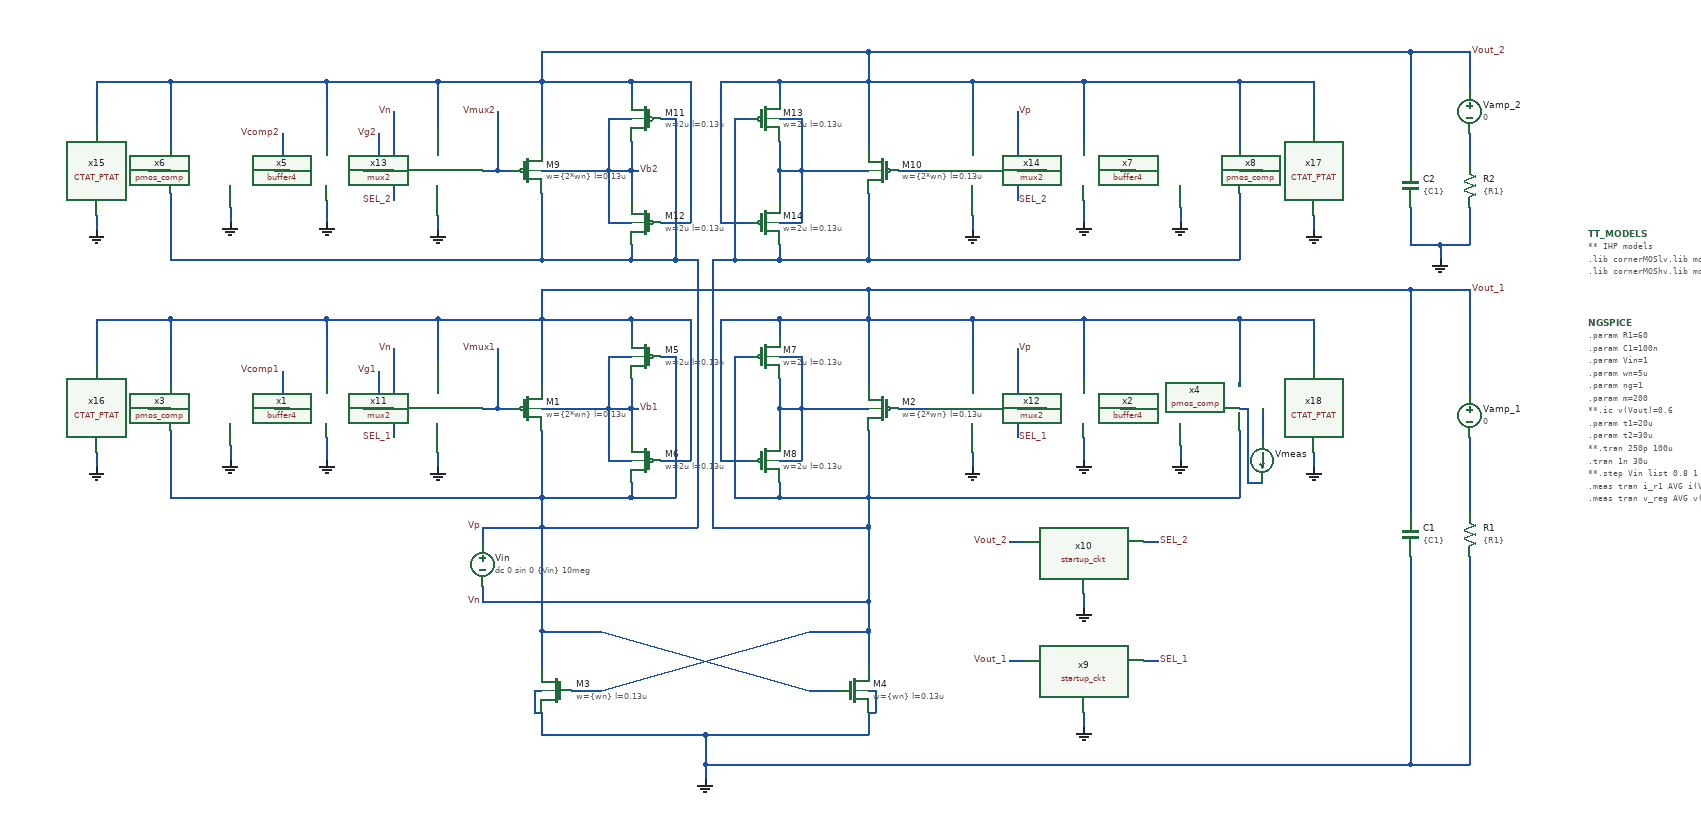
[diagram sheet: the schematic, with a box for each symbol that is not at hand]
v {xschem version=3.4.7 file_version=1.2}
G {}
K {}
V {}
S {}
E {}
P 4 1 1260 -1420 {}
N 870 -750 870 -730 {lab=Vout_1}
N 870 -530 870 -510 {lab=Vp}
N 910 -700 930 -700 {lab=Vp}
N 910 -560 950 -560 {lab=Vout_1}
N 1010 -700 1030 -700 {lab=Vn}
N 1070 -530 1070 -510 {lab=Vn}
N 1070 -750 1070 -730 {lab=Vout_1}
N 990 -560 1030 -560 {lab=Vout_1}
N 1070 -630 1070 -590 {lab=#net1}
N 1070 -670 1070 -630 {lab=#net1}
N 870 -630 870 -590 {lab=Vb1}
N 840 -630 870 -630 {lab=Vb1}
N 870 -670 870 -630 {lab=Vb1}
N 750 -750 870 -750 {lab=Vout_1}
N 1070 -750 1190 -750 {lab=Vout_1}
N 750 -750 750 -660 {lab=Vout_1}
N 1190 -750 1190 -660 {lab=Vout_1}
N 930 -700 930 -510 {lab=Vp}
N 870 -510 930 -510 {lab=Vp}
N 750 -510 870 -510 {lab=Vp}
N 750 -600 750 -510 {lab=Vp}
N 1070 -510 1190 -510 {lab=Vn}
N 1190 -600 1190 -510 {lab=Vn}
N 1010 -700 1010 -510 {lab=Vn}
N 1010 -510 1070 -510 {lab=Vn}
N 990 -750 990 -560 {lab=Vout_1}
N 990 -750 1070 -750 {lab=Vout_1}
N 950 -750 950 -560 {lab=Vout_1}
N 870 -750 950 -750 {lab=Vout_1}
N 970 -190 1190 -190 {lab=GND}
N 1190 -330 1190 -280 {lab=Vn}
N 750 -330 750 -280 {lab=Vp}
N 790 -250 830 -250 {lab=Vn}
N 1110 -250 1150 -250 {lab=Vp}
N 830 -250 1110 -330 {lab=Vn}
N 830 -330 1110 -250 {lab=Vp}
N 750 -330 830 -330 {lab=Vp}
N 750 -470 750 -330 {lab=Vp}
N 1110 -330 1190 -330 {lab=Vn}
N 1190 -370 1190 -330 {lab=Vn}
N 670 -390 670 -370 {lab=Vn}
N 670 -370 1190 -370 {lab=Vn}
N 1190 -470 1190 -370 {lab=Vn}
N 670 -470 670 -450 {lab=Vp}
N 670 -470 750 -470 {lab=Vp}
N 750 -510 750 -470 {lab=Vp}
N 840 -700 870 -700 {lab=Vb1}
N 840 -700 840 -630 {lab=Vb1}
N 840 -560 870 -560 {lab=Vb1}
N 840 -630 840 -560 {lab=Vb1}
N 1070 -700 1100 -700 {lab=#net1}
N 1100 -700 1100 -630 {lab=#net1}
N 1070 -630 1100 -630 {lab=#net1}
N 1070 -560 1100 -560 {lab=#net1}
N 1100 -630 1100 -560 {lab=#net1}
N 400 -630 410 -630 {lab=Vcomp1}
N 250 -600 250 -510 {lab=Vp}
N 250 -750 250 -660 {lab=Vout_1}
N 460 -750 460 -670 {lab=Vout_1}
N 250 -750 460 -750 {lab=Vout_1}
N 750 -790 750 -750 {lab=Vout_1}
N 750 -790 1190 -790 {lab=Vout_1}
N 1190 -790 1190 -750 {lab=Vout_1}
N 970 -150 970 -130 {lab=GND}
N 750 -190 970 -190 {lab=GND}
N 1920 -430 1920 -150 {lab=GND}
N 2000 -430 2000 -150 {lab=GND}
N 1920 -150 2000 -150 {lab=GND}
N 1920 -790 1920 -490 {lab=Vout_1}
N 2000 -590 2000 -490 {lab=#net2}
N 2000 -790 2000 -650 {lab=Vout_1}
N 1190 -250 1200 -250 {lab=GND}
N 1200 -250 1200 -220 {lab=GND}
N 1190 -220 1200 -220 {lab=GND}
N 1190 -220 1190 -190 {lab=GND}
N 750 -220 750 -190 {lab=GND}
N 740 -250 750 -250 {lab=GND}
N 740 -250 740 -220 {lab=GND}
N 740 -220 750 -220 {lab=GND}
N 1100 -630 1190 -630 {lab=#net1}
N 750 -630 840 -630 {lab=Vb1}
N 530 -680 530 -630 {lab=Vg1}
N 510 -630 530 -630 {lab=Vg1}
N 400 -680 400 -630 {lab=Vcomp1}
N 390 -630 400 -630 {lab=Vcomp1}
N 870 -630 880 -630 {lab=Vb1}
N 460 -590 460 -560 {lab=GND}
N 330 -580 330 -560 {lab=GND}
N 250 -510 750 -510 {lab=Vp}
N 610 -750 750 -750 {lab=Vout_1}
N 530 -630 550 -630 {lab=Vg1}
N 550 -710 550 -650 {lab=Vn}
N 550 -610 550 -590 {lab=SEL_1}
N 690 -630 710 -630 {lab=Vmux1}
N 690 -710 690 -630 {lab=Vmux1}
N 670 -630 690 -630 {lab=Vmux1}
N 610 -570 610 -550 {lab=GND}
N 610 -750 610 -690 {lab=Vout_1}
N 460 -750 610 -750 {lab=Vout_1}
N 1530 -630 1550 -630 {lab=#net3}
N 1690 -600 1690 -510 {lab=Vn}
N 1690 -750 1690 -660 {lab=Vout_1}
N 1480 -750 1480 -670 {lab=Vout_1}
N 1480 -750 1690 -750 {lab=Vout_1}
N 1480 -590 1480 -560 {lab=GND}
N 1610 -580 1610 -560 {lab=GND}
N 1190 -510 1690 -510 {lab=Vn}
N 1190 -750 1330 -750 {lab=Vout_1}
N 1390 -630 1430 -630 {lab=#net4}
N 1390 -610 1390 -590 {lab=SEL_1}
N 1230 -630 1270 -630 {lab=#net5}
N 1330 -570 1330 -550 {lab=GND}
N 1330 -750 1330 -690 {lab=Vout_1}
N 1330 -750 1480 -750 {lab=Vout_1}
N 1390 -710 1390 -650 {lab=Vp}
N 870 -1070 870 -1050 {lab=Vout_2}
N 870 -850 870 -830 {lab=Vp}
N 910 -1020 930 -1020 {lab=Vp}
N 910 -880 950 -880 {lab=Vout_2}
N 1010 -1020 1030 -1020 {lab=Vn}
N 1070 -850 1070 -830 {lab=Vn}
N 1070 -1070 1070 -1050 {lab=Vout_2}
N 990 -880 1030 -880 {lab=Vout_2}
N 1070 -950 1070 -910 {lab=#net6}
N 1070 -990 1070 -950 {lab=#net6}
N 870 -950 870 -910 {lab=Vb2}
N 840 -950 870 -950 {lab=Vb2}
N 870 -990 870 -950 {lab=Vb2}
N 750 -1070 870 -1070 {lab=Vout_2}
N 1070 -1070 1190 -1070 {lab=Vout_2}
N 750 -1070 750 -980 {lab=Vout_2}
N 1190 -1070 1190 -980 {lab=Vout_2}
N 930 -1020 930 -830 {lab=Vp}
N 870 -830 930 -830 {lab=Vp}
N 750 -830 870 -830 {lab=Vp}
N 750 -920 750 -830 {lab=Vp}
N 1070 -830 1190 -830 {lab=Vn}
N 1190 -920 1190 -830 {lab=Vn}
N 1010 -1020 1010 -830 {lab=Vn}
N 1010 -830 1070 -830 {lab=Vn}
N 990 -1070 990 -880 {lab=Vout_2}
N 990 -1070 1070 -1070 {lab=Vout_2}
N 950 -1070 950 -880 {lab=Vout_2}
N 870 -1070 950 -1070 {lab=Vout_2}
N 840 -1020 870 -1020 {lab=Vb2}
N 840 -1020 840 -950 {lab=Vb2}
N 840 -880 870 -880 {lab=Vb2}
N 840 -950 840 -880 {lab=Vb2}
N 1070 -1020 1100 -1020 {lab=#net6}
N 1100 -1020 1100 -950 {lab=#net6}
N 1070 -950 1100 -950 {lab=#net6}
N 1070 -880 1100 -880 {lab=#net6}
N 1100 -950 1100 -880 {lab=#net6}
N 400 -950 410 -950 {lab=Vcomp2}
N 250 -920 250 -830 {lab=Vp}
N 250 -1070 250 -980 {lab=Vout_2}
N 460 -1070 460 -990 {lab=Vout_2}
N 1100 -950 1190 -950 {lab=#net6}
N 750 -950 840 -950 {lab=Vb2}
N 530 -1000 530 -950 {lab=Vg2}
N 510 -950 530 -950 {lab=Vg2}
N 400 -1000 400 -950 {lab=Vcomp2}
N 390 -950 400 -950 {lab=Vcomp2}
N 870 -950 880 -950 {lab=Vb2}
N 460 -910 460 -880 {lab=GND}
N 330 -900 330 -880 {lab=GND}
N 250 -830 750 -830 {lab=Vp}
N 610 -1070 750 -1070 {lab=Vout_2}
N 530 -950 550 -950 {lab=Vg2}
N 550 -1030 550 -970 {lab=Vn}
N 550 -930 550 -910 {lab=SEL_2}
N 690 -950 710 -950 {lab=Vmux2}
N 690 -1030 690 -950 {lab=Vmux2}
N 670 -950 690 -950 {lab=Vmux2}
N 610 -890 610 -870 {lab=GND}
N 610 -1070 610 -1010 {lab=Vout_2}
N 460 -1070 610 -1070 {lab=Vout_2}
N 1530 -950 1550 -950 {lab=#net7}
N 1690 -920 1690 -830 {lab=Vn}
N 1690 -1070 1690 -980 {lab=Vout_2}
N 1480 -1070 1480 -990 {lab=Vout_2}
N 1480 -1070 1690 -1070 {lab=Vout_2}
N 1480 -910 1480 -880 {lab=GND}
N 1610 -900 1610 -880 {lab=GND}
N 1190 -830 1690 -830 {lab=Vn}
N 1190 -1070 1330 -1070 {lab=Vout_2}
N 1390 -950 1430 -950 {lab=#net8}
N 1390 -930 1390 -910 {lab=SEL_2}
N 1230 -950 1270 -950 {lab=#net9}
N 1330 -890 1330 -870 {lab=GND}
N 1330 -1070 1330 -1010 {lab=Vout_2}
N 1330 -1070 1480 -1070 {lab=Vout_2}
N 1390 -1030 1390 -970 {lab=Vp}
N 750 -470 960 -470 {lab=Vp}
N 930 -830 960 -830 {lab=Vp}
N 960 -830 960 -470 {lab=Vp}
N 980 -830 1010 -830 {lab=Vn}
N 980 -830 980 -470 {lab=Vn}
N 980 -470 1190 -470 {lab=Vn}
N 1190 -510 1190 -470 {lab=Vn}
N 1960 -850 2000 -850 {lab=GND}
N 1960 -850 1960 -830 {lab=GND}
N 1920 -850 1960 -850 {lab=GND}
N 970 -190 970 -150 {lab=GND}
N 1480 -380 1480 -360 {lab=GND}
N 1480 -220 1480 -200 {lab=GND}
N 1380 -290 1400 -290 {lab=Vout_1}
N 1380 -450 1400 -450 {lab=Vout_2}
N 1560 -450 1580 -450 {lab=SEL_2}
N 1560 -290 1580 -290 {lab=SEL_1}
N 2000 -900 2000 -850 {lab=GND}
N 1920 -900 1920 -850 {lab=GND}
N 1920 -1110 1920 -960 {lab=Vout_2}
N 2000 -1000 2000 -960 {lab=#net10}
N 2000 -1110 2000 -1060 {lab=Vout_2}
N 750 -1110 750 -1070 {lab=Vout_2}
N 1190 -1110 1920 -1110 {lab=Vout_2}
N 1190 -1110 1190 -1070 {lab=Vout_2}
N 750 -1110 1190 -1110 {lab=Vout_2}
N 150 -570 150 -550 {lab=GND}
N 150 -750 150 -690 {lab=Vout_1}
N 150 -750 250 -750 {lab=Vout_1}
N 220 -630 250 -630 {lab=#net11}
N 1790 -570 1790 -550 {lab=GND}
N 1190 -790 1920 -790 {lab=Vout_1}
N 1920 -790 2000 -790 {lab=Vout_1}
N 970 -150 1920 -150 {lab=GND}
N 1920 -1110 2000 -1110 {lab=Vout_2}
N 150 -890 150 -870 {lab=GND}
N 150 -1070 150 -1010 {lab=Vout_2}
N 250 -1070 460 -1070 {lab=Vout_2}
N 150 -1070 250 -1070 {lab=Vout_2}
N 220 -950 250 -950 {lab=#net12}
N 1790 -890 1790 -870 {lab=GND}
N 1790 -1070 1790 -1010 {lab=Vout_2}
N 1690 -1070 1790 -1070 {lab=Vout_2}
N 1690 -950 1720 -950 {lab=#net13}
N 1790 -750 1790 -690 {lab=Vout_1}
N 1690 -750 1790 -750 {lab=Vout_1}
N 1720 -630 1720 -590 {lab=#net14}
N 1700 -530 1720 -530 {lab=#net15}
N 1700 -630 1700 -530 {lab=#net15}
N 1690 -630 1700 -630 {lab=#net15}
C {sg13g2_pr/sg13_lv_pmos.sym} 730 -630 0 0 {name=M1
l=0.13u
w=\{2*wn\}
ng=\{ng\}
m=\{m\}
model=sg13_lv_pmos
spiceprefix=X
}
C {sg13g2_pr/sg13_lv_pmos.sym} 1210 -630 0 1 {name=M2
l=0.13u
w=\{2*wn\}
ng=\{ng\}
m=\{m\}
model=sg13_lv_pmos
spiceprefix=X
}
C {sg13g2_pr/sg13_lv_nmos.sym} 770 -250 0 1 {name=M3
l=0.13u
w=\{wn\}
ng=\{ng\}
m=\{m\}
model=sg13_lv_nmos
spiceprefix=X
}
C {sg13g2_pr/sg13_lv_nmos.sym} 1170 -250 0 0 {name=M4
l=0.13u
w=\{wn\}
ng=\{ng\}
m=\{m\}
model=sg13_lv_nmos
spiceprefix=X
}
C {sg13g2_pr/sg13_lv_pmos.sym} 890 -700 0 1 {name=M5
l=0.13u
w=2u
ng=1
m=1
model=sg13_lv_pmos
spiceprefix=X
}
C {sg13g2_pr/sg13_lv_pmos.sym} 890 -560 2 0 {name=M6
l=0.13u
w=2u
ng=1
m=1
model=sg13_lv_pmos
spiceprefix=X
}
C {sg13g2_pr/sg13_lv_pmos.sym} 1050 -700 0 0 {name=M7
l=0.13u
w=2u
ng=1
m=1
model=sg13_lv_pmos
spiceprefix=X
}
C {sg13g2_pr/sg13_lv_pmos.sym} 1050 -560 2 1 {name=M8
l=0.13u
w=2u
ng=1
m=1
model=sg13_lv_pmos
spiceprefix=X
}
C {vsource.sym} 670 -420 0 1 {name=Vin value="dc 0 sin 0 \{Vin\} 10meg" savecurrent=false}
C {lab_pin.sym} 670 -470 0 0 {name=p1 sig_type=std_logic lab=Vp}
C {lab_pin.sym} 670 -370 0 0 {name=p2 sig_type=std_logic lab=Vn}
C {gnd.sym} 150 -550 0 0 {name=l1 lab=GND}
C {capa.sym} 1920 -460 0 0 {name=C1
m=1
value=\{C1\}
footprint=1206
device="ceramic capacitor"}
C {res.sym} 2000 -460 0 0 {name=R1
value=\{R1\}
footprint=1206
device=resistor
m=1}
C {vsource.sym} 2000 -620 0 0 {name=Vamp_1 value=0 savecurrent=false}
C {lab_pin.sym} 2000 -790 0 1 {name=p3 sig_type=std_logic lab=Vout_1}
C {gnd.sym} 970 -130 0 0 {name=l3 lab=GND}
C {lab_pin.sym} 400 -680 0 0 {name=p4 sig_type=std_logic lab=Vcomp1}
C {lab_pin.sym} 530 -680 0 0 {name=p5 sig_type=std_logic lab=Vg1}
C {lab_pin.sym} 880 -630 0 1 {name=p6 sig_type=std_logic lab=Vb1}
C {gnd.sym} 330 -560 0 0 {name=l4 lab=GND}
C {gnd.sym} 460 -560 0 0 {name=l5 lab=GND}
C {code_shown.sym} 2160 -865 0 0 {
name=TT_MODELS
only_toplevel=true
value="
** IHP models
.lib cornerMOSlv.lib mos_tt
.lib cornerMOShv.lib mos_tt
"
spice_ignore=false
      }
C {code_shown.sym} 2160 -745 0 0 {name=NGSPICE
only_toplevel=false
value="
.param R1=60
.param C1=100n
.param Vin=1
.param wn=5u
.param ng=1
.param m=200
**.ic v(Vout)=0.6
.param t1=20u
.param t2=30u
**.tran 250p 100u
.tran 1n 30u
**.step Vin list 0.8 1
.meas tran i_r1 AVG i(Vamp_1) from=t1 to=t2
.meas tran v_reg AVG v(vout_1) from=t1 to=t2
.meas tran p_out AVG par('((v(Vout_1)**2)/R1)+((v(Vout_2)**2)/R1)') from=t1 to=t2
.meas tran p_in AVG par('-(v(Vp)-v(Vn))*i(Vin)') from=t1 to=t2
.meas tran PCE param='p_out/p_in' from=t1 to=t2
.meas tran VCR param='v_reg/Vin'
.save all
"}
C {lab_pin.sym} 550 -590 0 0 {name=p7 sig_type=std_logic lab=SEL_1}
C {lab_pin.sym} 550 -710 0 0 {name=p8 sig_type=std_logic lab=Vn}
C {lab_pin.sym} 690 -710 0 0 {name=p9 sig_type=std_logic lab=Vmux1}
C {gnd.sym} 610 -550 0 0 {name=l8 lab=GND}
C {gnd.sym} 1790 -550 0 1 {name=l2 lab=GND}
C {gnd.sym} 1610 -560 0 1 {name=l6 lab=GND}
C {gnd.sym} 1480 -560 0 1 {name=l7 lab=GND}
C {lab_pin.sym} 1390 -590 0 1 {name=p12 sig_type=std_logic lab=SEL_1}
C {gnd.sym} 1330 -550 0 1 {name=l9 lab=GND}
C {lab_pin.sym} 1390 -710 0 1 {name=p10 sig_type=std_logic lab=Vp}
C {sg13g2_pr/sg13_lv_pmos.sym} 730 -950 0 0 {name=M9
l=0.13u
w=\{2*wn\}
ng=\{ng\}
m=\{m\}
model=sg13_lv_pmos
spiceprefix=X
}
C {sg13g2_pr/sg13_lv_pmos.sym} 1210 -950 0 1 {name=M10
l=0.13u
w=\{2*wn\}
ng=\{ng\}
m=\{m\}
model=sg13_lv_pmos
spiceprefix=X
}
C {sg13g2_pr/sg13_lv_pmos.sym} 890 -1020 0 1 {name=M11
l=0.13u
w=2u
ng=1
m=1
model=sg13_lv_pmos
spiceprefix=X
}
C {sg13g2_pr/sg13_lv_pmos.sym} 890 -880 2 0 {name=M12
l=0.13u
w=2u
ng=1
m=1
model=sg13_lv_pmos
spiceprefix=X
}
C {sg13g2_pr/sg13_lv_pmos.sym} 1050 -1020 0 0 {name=M13
l=0.13u
w=2u
ng=1
m=1
model=sg13_lv_pmos
spiceprefix=X
}
C {sg13g2_pr/sg13_lv_pmos.sym} 1050 -880 2 1 {name=M14
l=0.13u
w=2u
ng=1
m=1
model=sg13_lv_pmos
spiceprefix=X
}
C {lab_pin.sym} 400 -1000 0 0 {name=p11 sig_type=std_logic lab=Vcomp2}
C {lab_pin.sym} 530 -1000 0 0 {name=p13 sig_type=std_logic lab=Vg2}
C {lab_pin.sym} 880 -950 0 1 {name=p14 sig_type=std_logic lab=Vb2}
C {gnd.sym} 330 -880 0 0 {name=l11 lab=GND}
C {gnd.sym} 460 -880 0 0 {name=l12 lab=GND}
C {lab_pin.sym} 550 -910 0 0 {name=p15 sig_type=std_logic lab=SEL_2}
C {lab_pin.sym} 550 -1030 0 0 {name=p16 sig_type=std_logic lab=Vn}
C {lab_pin.sym} 690 -1030 0 0 {name=p17 sig_type=std_logic lab=Vmux2}
C {gnd.sym} 610 -870 0 0 {name=l13 lab=GND}
C {gnd.sym} 1610 -880 0 1 {name=l14 lab=GND}
C {gnd.sym} 1480 -880 0 1 {name=l15 lab=GND}
C {lab_pin.sym} 1390 -910 0 1 {name=p18 sig_type=std_logic lab=SEL_2}
C {gnd.sym} 1330 -870 0 1 {name=l16 lab=GND}
C {lab_pin.sym} 1390 -1030 0 1 {name=p19 sig_type=std_logic lab=Vp}
C {capa.sym} 1920 -930 0 0 {name=C2
m=1
value=\{C1\}
footprint=1206
device="ceramic capacitor"}
C {res.sym} 2000 -930 0 0 {name=R2
value=\{R1\}
footprint=1206
device=resistor
m=1}
C {vsource.sym} 2000 -1030 0 0 {name=Vamp_2 value=0 savecurrent=false}
C {gnd.sym} 1960 -830 0 1 {name=l18 lab=GND}
C {lab_pin.sym} 2000 -1110 0 1 {name=p20 sig_type=std_logic lab=Vout_2}
C {gnd.sym} 1480 -360 0 1 {name=l19 lab=GND}
C {gnd.sym} 1480 -200 0 1 {name=l20 lab=GND}
C {lab_pin.sym} 1380 -290 0 0 {name=p21 sig_type=std_logic lab=Vout_1}
C {lab_pin.sym} 1380 -450 0 0 {name=p22 sig_type=std_logic lab=Vout_2}
C {lab_pin.sym} 1580 -290 0 1 {name=p23 sig_type=std_logic lab=SEL_1}
C {lab_pin.sym} 1580 -450 0 1 {name=p24 sig_type=std_logic lab=SEL_2}
C {gnd.sym} 150 -870 0 0 {name=l10 lab=GND}
C {gnd.sym} 1790 -870 0 1 {name=l17 lab=GND}
C {SSDOR_1V_v1/components/buffer4/buffer4.sym} 390 -550 0 0 {name=x1 wn=1u}
C {SSDOR_1V_v1/components/buffer4/buffer4.sym} 1550 -550 0 1 {name=x2 wn=1u}
C {SSDOR_1V_v1/components/buffer4/buffer4.sym} 390 -870 0 0 {name=x5 wn=1u}
C {SSDOR_1V_v1/components/buffer4/buffer4.sym} 1550 -870 0 1 {name=x7 wn=1u}
C {SSDOR_1V_v1/components/pmos_comp/pmos_comp.sym} 230 -560 0 0 {name=x3}
C {SSDOR_1V_v1/components/pmos_comp/pmos_comp.sym} 1710 -560 0 1 {name=x4}
C {SSDOR_1V_v1/components/pmos_comp/pmos_comp.sym} 230 -880 0 0 {name=x6}
C {SSDOR_1V_v1/components/pmos_comp/pmos_comp.sym} 1710 -880 0 1 {name=x8}
C {SSDOR_1V_v1/components/mux2/mux2.sym} 610 -630 0 0 {name=x11}
C {SSDOR_1V_v1/components/mux2/mux2.sym} 1330 -630 0 1 {name=x12}
C {SSDOR_1V_v1/components/mux2/mux2.sym} 610 -950 0 0 {name=x13}
C {SSDOR_1V_v1/components/mux2/mux2.sym} 1330 -950 0 1 {name=x14}
C {SSDOR_1V_v1/components/startup_ckt/startup_ckt.sym} 1480 -270 0 0 {name=x9}
C {SSDOR_1V_v1/components/startup_ckt/startup_ckt.sym} 1480 -430 0 0 {name=x10}
C {ammeter.sym} 1720 -560 0 0 {name=Vmeas savecurrent=true spice_ignore=0}
C {SSDOR_1V_v1/components/Ib_4u/CTAT_PTAT/CTAT_PTAT.sym} 110 -890 0 0 {name=x15}
C {SSDOR_1V_v1/components/Ib_4u/CTAT_PTAT/CTAT_PTAT.sym} 110 -570 0 0 {name=x16}
C {SSDOR_1V_v1/components/Ib_4u/CTAT_PTAT/CTAT_PTAT.sym} 1830 -890 0 1 {name=x17}
C {SSDOR_1V_v1/components/Ib_4u/CTAT_PTAT/CTAT_PTAT.sym} 1830 -570 0 1 {name=x18}
